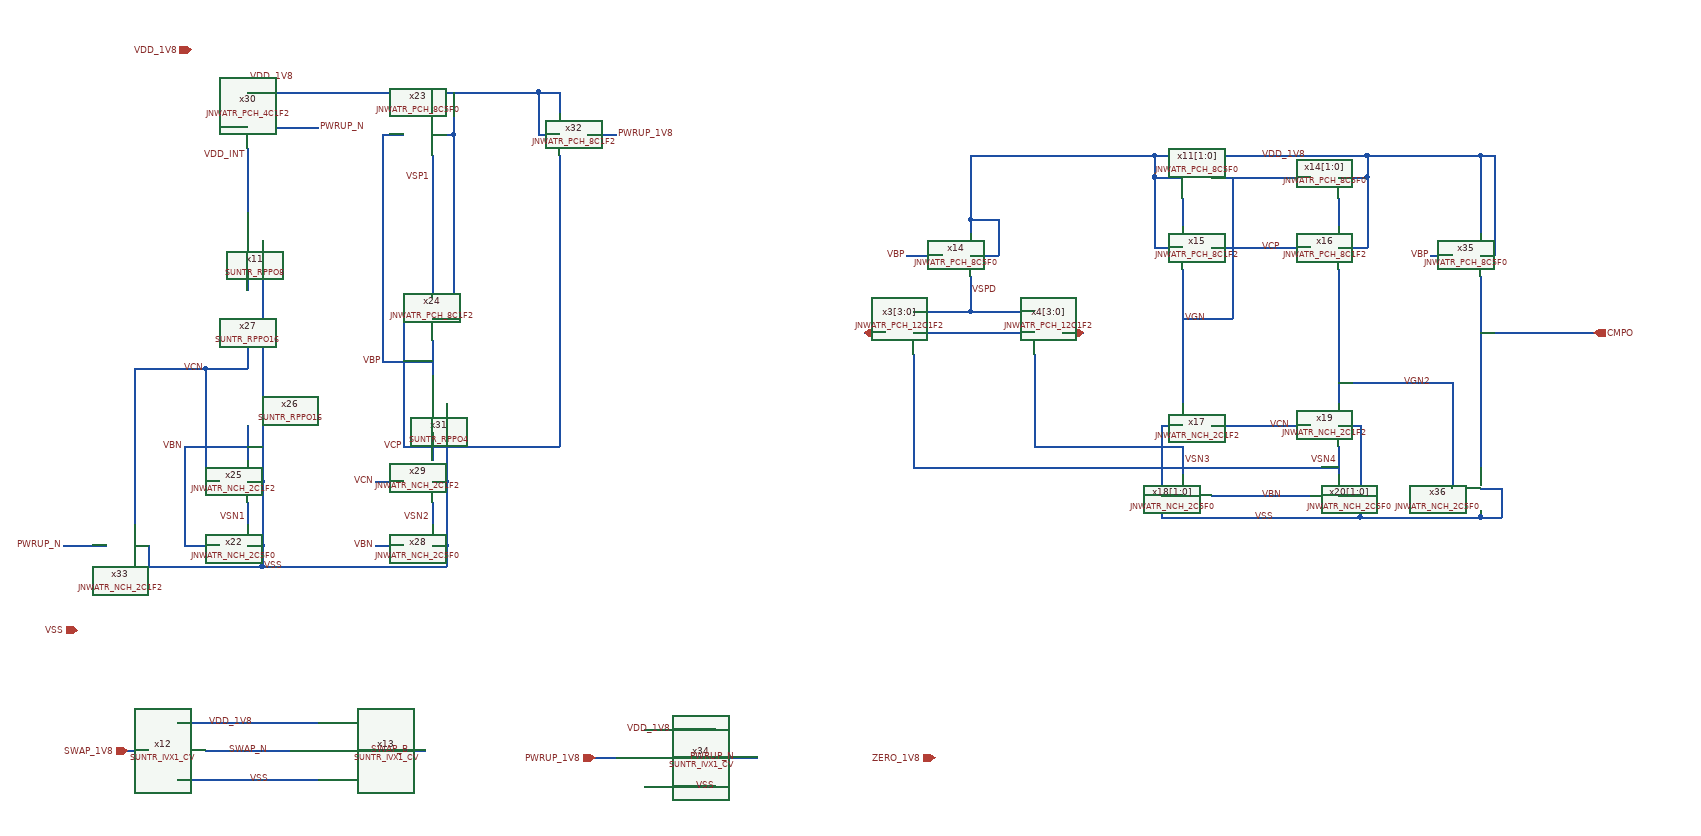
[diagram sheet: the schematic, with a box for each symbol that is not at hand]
v {xschem version=3.4.5 file_version=1.2
}
G {}
K {}
V {}
S {}
E {}
N 360 -610 460 -610 {
lab=VDD_1V8}
N 360 -530 460 -530 {
lab=VSS}
N 400 -570 420 -570 {
lab=SWAP_N}
N 290 -570 320 -570 {
lab=SWAP_1V8}
N 460 -530 560 -530 {
lab=VSS}
N 460 -610 550 -610 {
lab=VDD_1V8}
N 420 -570 520 -570 {
lab=SWAP_N}
N 600 -570 710 -570 {
lab=SWAP_B}
N 1740 -1380 1780 -1380 {
lab=VDD_1V8}
N 1740 -1410 1740 -1380 {
lab=VDD_1V8}
N 1740 -1410 1780 -1410 {
lab=VDD_1V8}
N 1780 -1410 2000 -1410 {
lab=VDD_1V8}
N 2000 -1380 2040 -1380 {
lab=VDD_1V8}
N 2040 -1410 2040 -1380 {
lab=VDD_1V8}
N 2000 -1410 2040 -1410 {
lab=VDD_1V8}
N 2000 -1350 2000 -1310 {
lab=#net1}
N 1780 -1350 1780 -1310 {
lab=#net2}
N 1740 -1280 1780 -1280 {
lab=VDD_1V8}
N 1740 -1380 1740 -1280 {
lab=VDD_1V8}
N 2000 -1280 2040 -1280 {
lab=VDD_1V8}
N 2040 -1380 2040 -1280 {
lab=VDD_1V8}
N 1780 -1000 1780 -960 {
lab=VSN3}
N 1750 -1030 1780 -1030 {
lab=VSS}
N 1750 -1030 1750 -900 {
lab=VSS}
N 1750 -900 1780 -900 {
lab=VSS}
N 1750 -930 1780 -930 {
lab=VSS}
N 2000 -1000 2000 -960 {
lab=VSN4}
N 2000 -1030 2030 -1030 {
lab=VSS}
N 2030 -1030 2030 -900 {
lab=VSS}
N 2000 -900 2030 -900 {
lab=VSS}
N 2000 -930 2030 -930 {
lab=VSS}
N 1780 -1250 1780 -1060 {
lab=VGN}
N 1780 -900 2000 -900 {
lab=VSS}
N 1820 -930 1860 -930 {
lab=VBN}
N 1820 -1030 1960 -1030 {
lab=VCN}
N 1820 -1280 1960 -1280 {
lab=VCP}
N 1820 -1380 1960 -1380 {
lab=VGN}
N 460 -920 460 -890 {
lab=VSN1}
N 460 -860 480 -860 {
lab=VSS}
N 480 -860 480 -830 {
lab=VSS}
N 460 -830 480 -830 {
lab=VSS}
N 480 -950 480 -860 {
lab=VSS}
N 460 -950 480 -950 {
lab=VSS}
N 460 -1030 460 -980 {
lab=VBN}
N 370 -860 420 -860 {
lab=VBN}
N 370 -1000 370 -860 {
lab=VBN}
N 370 -1000 460 -1000 {
lab=VBN}
N 400 -950 420 -950 {
lab=VCN}
N 400 -1110 400 -950 {
lab=VCN}
N 400 -1110 460 -1110 {
lab=VCN}
N 480 -1070 480 -950 {
lab=VSS}
N 480 -1180 480 -1070 {
lab=VSS}
N 460 -1140 460 -1110 {
lab=VCN}
N 420 -1450 460 -1450 {
lab=VDD_1V8}
N 420 -1480 420 -1450 {
lab=VDD_1V8}
N 420 -1480 460 -1480 {
lab=VDD_1V8}
N 460 -1520 460 -1480 {
lab=VDD_1V8}
N 500 -1450 560 -1450 {
lab=PWRUP_N}
N 720 -920 720 -890 {
lab=VSN2}
N 720 -950 740 -950 {
lab=VSS}
N 740 -950 740 -860 {
lab=VSS}
N 720 -860 740 -860 {
lab=VSS}
N 720 -830 740 -830 {
lab=VSS}
N 740 -860 740 -830 {
lab=VSS}
N 640 -950 680 -950 {
lab=VCN}
N 640 -860 680 -860 {
lab=VBN}
N 740 -1060 740 -950 {
lab=VSS}
N 720 -1020 720 -980 {
lab=VCP}
N 720 -1150 720 -1100 {
lab=VBP}
N 720 -1180 750 -1180 {
lab=VDD_1V8}
N 750 -1280 750 -1180 {
lab=VDD_1V8}
N 720 -1440 750 -1440 {
lab=VDD_1V8}
N 750 -1470 750 -1440 {
lab=VDD_1V8}
N 720 -1410 720 -1370 {
lab=VSP1}
N 680 -1180 680 -1000 {
lab=VCP}
N 680 -1000 720 -1000 {
lab=VCP}
N 650 -1120 720 -1120 {
lab=VBP}
N 650 -1280 650 -1120 {
lab=VBP}
N 650 -1440 680 -1440 {
lab=VBP}
N 460 -1500 720 -1500 {
lab=VDD_1V8}
N 720 -1500 720 -1470 {
lab=VDD_1V8}
N 900 -1260 900 -1000 {
lab=VCP}
N 720 -1000 900 -1000 {
lab=VCP}
N 870 -1440 900 -1440 {
lab=VDD_1V8}
N 870 -1500 870 -1440 {
lab=VDD_1V8}
N 870 -1500 900 -1500 {
lab=VDD_1V8}
N 900 -1500 900 -1470 {
lab=VDD_1V8}
N 720 -1500 870 -1500 {
lab=VDD_1V8}
N 940 -1440 980 -1440 {
lab=PWRUP_1V8}
N 300 -830 460 -830 {
lab=VSS}
N 300 -860 320 -860 {
lab=VSS}
N 320 -860 320 -830 {
lab=VSS}
N 300 -1110 300 -890 {
lab=VCN}
N 300 -1110 400 -1110 {
lab=VCN}
N 200 -860 260 -860 {
lab=PWRUP_N}
N 480 -830 720 -830 {
lab=VSS}
N 1020 -600 1120 -600 {
lab=VDD_1V8}
N 1020 -520 1120 -520 {
lab=VSS}
N 1060 -560 1080 -560 {
lab=PWRUP_N}
N 950 -560 980 -560 {
lab=PWRUP_1V8}
N 1080 -560 1180 -560 {
lab=PWRUP_N}
N 1860 -930 1960 -930 {
lab=VBN}
N 750 -1500 750 -1470 {
lab=VDD_1V8}
N 550 -610 560 -610 {
lab=VDD_1V8}
N 750 -1440 750 -1280 {
lab=VDD_1V8}
N 720 -1370 720 -1210 {
lab=VSP1}
N 900 -1410 900 -1260 {
lab=VCP}
N 460 -1250 460 -1220 {
lab=#net3}
N 480 -1290 480 -1180 {
lab=VSS}
N 650 -1440 650 -1280 {
lab=VBP}
N 460 -1340 460 -1330 {
lab=VDD_INT}
N 460 -1420 460 -1400 {
lab=VDD_INT}
N 2000 -1120 2000 -1060 {
lab=VGN2}
N 2000 -1250 2000 -1200 {
lab=VGN2}
N 2200 -1410 2200 -1300 {
lab=VDD_1V8}
N 2040 -1410 2200 -1410 {
lab=VDD_1V8}
N 2200 -1270 2220 -1270 {
lab=VDD_1V8}
N 2220 -1410 2220 -1270 {
lab=VDD_1V8}
N 2200 -1410 2220 -1410 {
lab=VDD_1V8}
N 2200 -910 2200 -900 {
lab=VSS}
N 2030 -900 2200 -900 {
lab=VSS}
N 2200 -940 2230 -940 {
lab=VSS}
N 2230 -940 2230 -900 {
lab=VSS}
N 2200 -900 2230 -900 {
lab=VSS}
N 2200 -1000 2200 -970 {
lab=CMPO}
N 2200 -1240 2200 -1000 {
lab=CMPO}
N 2200 -1160 2360 -1160 {
lab=CMPO}
N 2130 -1270 2160 -1270 {
lab=VBP}
N 2160 -1090 2160 -940 {
lab=VGN2}
N 2000 -1090 2160 -1090 {
lab=VGN2}
N 2000 -1200 2000 -1120 {
lab=VGN2}
N 1480 -1270 1520 -1270 {
lab=VDD_1V8}
N 1520 -1320 1520 -1270 {
lab=VDD_1V8}
N 1480 -1320 1520 -1320 {
lab=VDD_1V8}
N 1480 -1320 1480 -1300 {
lab=VDD_1V8}
N 1480 -1240 1480 -1190 {
lab=VSPD}
N 1400 -1190 1480 -1190 {
lab=VSPD}
N 1480 -1190 1570 -1190 {
lab=VSPD}
N 1400 -1160 1570 -1160 {
lab=#net4}
N 1520 -1410 1740 -1410 {
lab=VDD_1V8}
N 1570 -1130 1570 -1000 {
lab=VSN3}
N 1570 -1000 1780 -1000 {
lab=VSN3}
N 1400 -1130 1400 -970 {
lab=VSN4}
N 1400 -970 2000 -970 {
lab=VSN4}
N 1390 -1270 1440 -1270 {
lab=VBP}
N 460 -1400 460 -1340 {
lab=VDD_INT}
N 1480 -1410 1480 -1320 {
lab=VDD_1V8}
N 1480 -1410 1520 -1410 {
lab=VDD_1V8}
N 1850 -1380 1850 -1180 {
lab=VGN}
N 1780 -1180 1850 -1180 {
lab=VGN}
N 1610 -1160 1640 -1160 {}
N 1330 -1160 1360 -1160 {}
C {devices/ipin.sym} 290 -570 0 0 {name=p10 lab=SWAP_1V8}
C {SUN_TR_SKY130NM/SUNTR_IVX1_CV.sym} 320 -570 0 0 {name=x12 }
C {SUN_TR_SKY130NM/SUNTR_IVX1_CV.sym} 520 -570 0 0 {name=x13 }
C {devices/lab_wire.sym} 470 -610 0 0 {name=p11 sig_type=std_logic lab=VDD_1V8}
C {devices/lab_wire.sym} 490 -570 0 0 {name=p12 sig_type=std_logic lab=SWAP_N}
C {devices/lab_wire.sym} 690 -570 0 0 {name=p13 sig_type=std_logic lab=SWAP_B}
C {devices/lab_wire.sym} 460 -530 0 1 {name=p14 sig_type=std_logic lab=VSS}
C {devices/ipin.sym} 1640 -1160 2 0 {name=p25 lab=VN}
C {devices/ipin.sym} 1330 -1160 2 1 {name=p26 lab=VP}
C {JNW_ATR_SKY130NM/JNWATR_PCH_8C5F0.sym} 1820 -1380 0 1 {name=x11[1:0]}
C {JNW_ATR_SKY130NM/JNWATR_PCH_8C5F0.sym} 1960 -1380 0 0 {name=x14[1:0]}
C {JNW_ATR_SKY130NM/JNWATR_PCH_8C1F2.sym} 1820 -1280 0 1 {name=x15 }
C {JNW_ATR_SKY130NM/JNWATR_PCH_8C1F2.sym} 1960 -1280 0 0 {name=x16 }
C {JNW_ATR_SKY130NM/JNWATR_NCH_2C1F2.sym} 1820 -1030 0 1 {name=x17 }
C {JNW_ATR_SKY130NM/JNWATR_NCH_2C5F0.sym} 1820 -930 0 1 {name=x18[1:0]}
C {JNW_ATR_SKY130NM/JNWATR_NCH_2C1F2.sym} 1960 -1030 0 0 {name=x19 }
C {JNW_ATR_SKY130NM/JNWATR_NCH_2C5F0.sym} 1960 -930 0 0 {name=x20[1:0]}
C {devices/lab_wire.sym} 1880 -900 0 1 {name=p9 sig_type=std_logic lab=VSS}
C {devices/lab_wire.sym} 1890 -1410 0 1 {name=p27 sig_type=std_logic lab=VDD_1V8}
C {devices/lab_wire.sym} 1900 -1030 0 1 {name=p28 sig_type=std_logic lab=VCN}
C {devices/lab_wire.sym} 1890 -1280 0 1 {name=p29 sig_type=std_logic lab=VCP}
C {JNW_ATR_SKY130NM/JNWATR_NCH_2C5F0.sym} 420 -860 0 0 {name=x22 }
C {JNW_ATR_SKY130NM/JNWATR_PCH_8C5F0.sym} 680 -1440 0 0 {name=x23 }
C {JNW_ATR_SKY130NM/JNWATR_PCH_8C1F2.sym} 680 -1180 0 0 {name=x24 }
C {JNW_ATR_SKY130NM/JNWATR_NCH_2C1F2.sym} 420 -950 0 0 {name=x25 }
C {SUN_TR_SKY130NM/SUNTR_RPPO16.sym} 460 -1030 3 0 {name=x26 }
C {SUN_TR_SKY130NM/SUNTR_RPPO16.sym} 460 -1140 3 0 {name=x27 }
C {devices/lab_wire.sym} 460 -1520 0 1 {name=p33 sig_type=std_logic lab=VDD_1V8}
C {devices/lab_wire.sym} 480 -830 0 1 {name=p34 sig_type=std_logic lab=VSS}
C {JNW_ATR_SKY130NM/JNWATR_NCH_2C5F0.sym} 680 -860 0 0 {name=x28 }
C {JNW_ATR_SKY130NM/JNWATR_NCH_2C1F2.sym} 680 -950 0 0 {name=x29 }
C {JNW_ATR_SKY130NM/JNWATR_PCH_4C1F2.sym} 500 -1450 0 1 {name=x30 }
C {devices/lab_wire.sym} 560 -1450 0 1 {name=p35 sig_type=std_logic lab=PWRUP_N}
C {devices/lab_wire.sym} 370 -1000 0 0 {name=p36 sig_type=std_logic lab=VBN}
C {devices/lab_wire.sym} 400 -1110 0 0 {name=p37 sig_type=std_logic lab=VCN}
C {devices/lab_wire.sym} 640 -950 0 0 {name=p38 sig_type=std_logic lab=VCN}
C {devices/lab_wire.sym} 640 -860 0 0 {name=p39 sig_type=std_logic lab=VBN}
C {SUN_TR_SKY130NM/SUNTR_RPPO4.sym} 720 -1020 3 0 {name=x31 }
C {devices/lab_wire.sym} 680 -1000 0 0 {name=p40 sig_type=std_logic lab=VCP}
C {devices/lab_wire.sym} 650 -1120 0 0 {name=p41 sig_type=std_logic lab=VBP}
C {JNW_ATR_SKY130NM/JNWATR_PCH_8C1F2.sym} 940 -1440 0 1 {name=x32 }
C {devices/lab_wire.sym} 980 -1440 0 1 {name=p42 sig_type=std_logic lab=PWRUP_1V8}
C {JNW_ATR_SKY130NM/JNWATR_NCH_2C1F2.sym} 260 -860 0 0 {name=x33 }
C {devices/lab_wire.sym} 200 -860 0 0 {name=p43 sig_type=std_logic lab=PWRUP_N}
C {devices/ipin.sym} 220 -740 0 0 {name=p45 lab=VSS}
C {devices/ipin.sym} 1430 -560 0 0 {name=p46 lab=ZERO_1V8}
C {devices/ipin.sym} 950 -560 0 0 {name=p47 lab=PWRUP_1V8}
C {SUN_TR_SKY130NM/SUNTR_IVX1_CV.sym} 980 -560 0 0 {name=x34 }
C {devices/lab_wire.sym} 1060 -600 0 0 {name=p48 sig_type=std_logic lab=VDD_1V8}
C {devices/lab_wire.sym} 1150 -560 0 0 {name=p49 sig_type=std_logic lab=PWRUP_N}
C {devices/lab_wire.sym} 1090 -520 0 1 {name=p51 sig_type=std_logic lab=VSS}
C {devices/opin.sym} 2360 -1160 0 0 {name=p50 lab=CMPO
}
C {devices/ipin.sym} 380 -1560 0 0 {name=p44 lab=VDD_1V8}
C {devices/lab_wire.sym} 460 -900 0 0 {name=p53 sig_type=std_logic lab=VSN1}
C {devices/lab_wire.sym} 720 -900 0 0 {name=p54 sig_type=std_logic lab=VSN2}
C {devices/lab_wire.sym} 720 -1380 0 0 {name=p55 sig_type=std_logic lab=VSP1}
C {devices/lab_wire.sym} 460 -1410 0 0 {name=p57 sig_type=std_logic lab=VDD_INT}
C {devices/lab_wire.sym} 1780 -1180 0 1 {name=p60 sig_type=std_logic lab=VGN}
C {devices/lab_wire.sym} 1780 -980 0 1 {name=p61 sig_type=std_logic lab=VSN3}
C {devices/lab_wire.sym} 2000 -980 0 0 {name=p62 sig_type=std_logic lab=VSN4}
C {SUN_TR_SKY130NM/SUNTR_RPPO8.sym} 460 -1250 3 0 {name=x11 }
C {JNW_ATR_SKY130NM/JNWATR_PCH_8C5F0.sym} 2160 -1270 0 0 {name=x35 }
C {JNW_ATR_SKY130NM/JNWATR_NCH_2C5F0.sym} 2160 -940 0 0 {name=x36 }
C {devices/lab_wire.sym} 2090 -1090 0 1 {name=p64 sig_type=std_logic lab=VGN2}
C {devices/lab_wire.sym} 2130 -1270 0 0 {name=p63 sig_type=std_logic lab=VBP}
C {JNW_ATR_SKY130NM/JNWATR_PCH_12C1F2.sym} 1360 -1160 0 0 {name=x3[3:0]}
C {JNW_ATR_SKY130NM/JNWATR_PCH_12C1F2.sym} 1610 -1160 0 1 {name=x4[3:0]}
C {JNW_ATR_SKY130NM/JNWATR_PCH_8C5F0.sym} 1440 -1270 0 0 {name=x14}
C {devices/lab_wire.sym} 1390 -1270 0 0 {name=p65 sig_type=std_logic lab=VBP}
C {devices/lab_wire.sym} 1480 -1220 0 1 {name=p66 sig_type=std_logic lab=VSPD}
C {devices/lab_wire.sym} 1890 -930 0 1 {name=p31 sig_type=std_logic lab=VBN}
